One B-rep face of a CAD part: STEP entity #274284.
In plain terms, the planar face has unit normal (0, 1, 0).
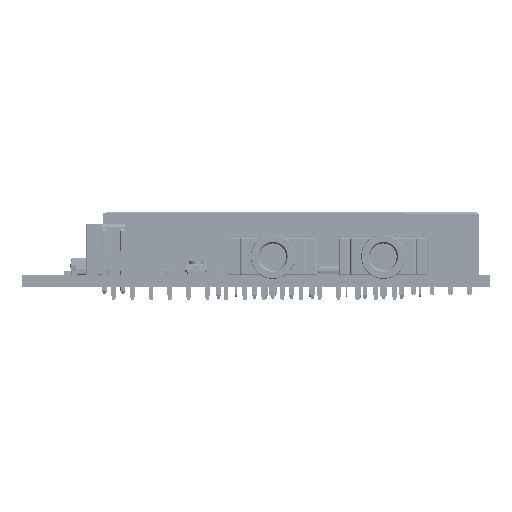
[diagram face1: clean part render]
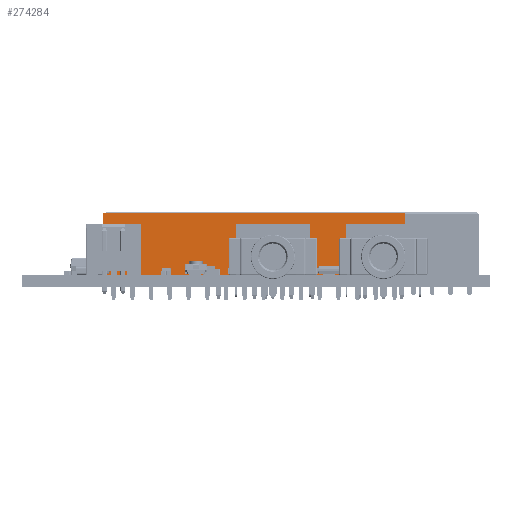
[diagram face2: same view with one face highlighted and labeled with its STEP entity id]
Its self-contained STEP definition (entity closure, numbers rounded to 3 decimals):
#258614=CARTESIAN_POINT('NONE',(20.52,1.25,0.));
#258789=VECTOR('NONE',#266806,1000.);
#260041 = LINE('NONE',#264456,#270153) ;
#260214=VECTOR('NONE',#276716,1000.);
#260476=CARTESIAN_POINT('NONE',(-20.52,1.25,8.5));
#261522=CARTESIAN_POINT('NONE',(-20.52,1.25,8.5));
#262454=DIRECTION('NONE',(0.,0.,-1.));
#263577=CARTESIAN_POINT('NONE',(20.52,1.25,8.5));
#263898 = PLANE('NONE',#267981) ;
#263899 = LINE('NONE',#276227,#258789) ;
#264235 = ORIENTED_EDGE('NONE',*,*,#280849,.T.) ;
#264456=CARTESIAN_POINT('NONE',(-20.52,1.25,8.5));
#265308 = LINE('NONE',#261522,#260214) ;
#265829 = EDGE_CURVE('NONE',#269785,#272831,#260041,.T.) ;
#265913=CARTESIAN_POINT('NONE',(-20.52,1.25,8.5));
#266806=DIRECTION('NONE',(-1.,0.,0.));
#267801=DIRECTION('NONE',(0.,0.,-1.));
#267981=AXIS2_PLACEMENT_3D('NONE',#265913,#279128,#267801);
#269391=CARTESIAN_POINT('NONE',(-20.52,1.25,0.));
#269785 = VERTEX_POINT('NONE',#260476) ;
#270153=VECTOR('NONE',#262454,1000.);
#271878 = ORIENTED_EDGE('NONE',*,*,#278360,.F.) ;
#272304=VECTOR('NONE',#275492,1000.);
#272831 = VERTEX_POINT('NONE',#269391) ;
#273019 = ORIENTED_EDGE('NONE',*,*,#277465,.T.) ;
#273622=CARTESIAN_POINT('NONE',(20.52,1.25,8.5));
#273646 = ORIENTED_EDGE('NONE',*,*,#265829,.F.) ;
#274284 = ADVANCED_FACE('NONE',(#281167),#263898,.F.) ;
#275344 = VERTEX_POINT('NONE',#263577) ;
#275492=DIRECTION('NONE',(0.,0.,-1.));
#276227=CARTESIAN_POINT('NONE',(-20.52,1.25,0.));
#276716=DIRECTION('NONE',(-1.,0.,0.));
#277297 = VERTEX_POINT('NONE',#258614) ;
#277465 = EDGE_CURVE('NONE',#277297,#272831,#263899,.T.) ;
#278360 = EDGE_CURVE('NONE',#275344,#269785,#265308,.T.) ;
#279128=DIRECTION('NONE',(0.,-1.,0.));
#279897 = EDGE_LOOP('NONE',(#273019,#273646,#271878,#264235)) ;
#280849 = EDGE_CURVE('NONE',#275344,#277297,#282370,.T.) ;
#281167 = FACE_OUTER_BOUND('NONE',#279897,.T.) ;
#282370 = LINE('NONE',#273622,#272304) ;
